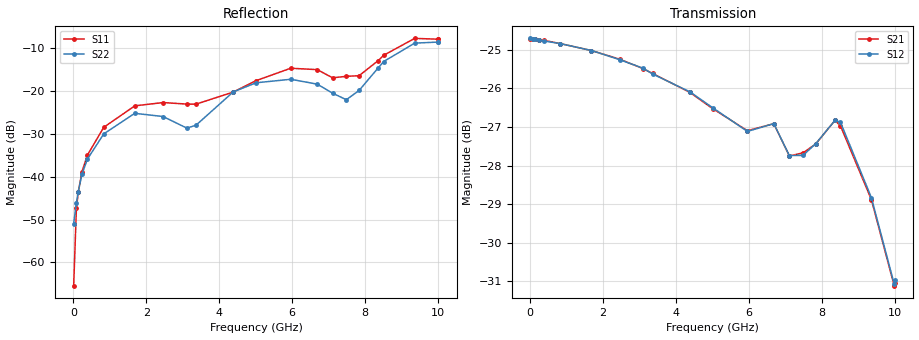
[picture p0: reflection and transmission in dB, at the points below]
! Device ID: PE43704
! Dir: z:\PE43704\PE43704_Char_1_20130516\PE43704\AMB\3p400V\23p75dB
! Serial: 14
! Insertion: A
! Impedance: 50 ohm
! Temp: Amb
! VDD: 3.400V
! Attenuation Step: 23.75dB
! IDD: 1.140316e-01mA
#  Hz  S  RI  R  50
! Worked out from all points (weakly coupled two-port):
!   401 points, 10 MHz to 10.01 GHz, reference 50 ohm
!   highest |S21| = -24.72 dB at 10 MHz (marker M1); lowest = -31.1 dB at 9.985 GHz (marker M2)
!   lowest |S11| = -65.4 dB at 10 MHz (marker M3), VSWR 1.00, Z = 50 + j0.0424 ohm
!   |S11| at or under -10 dB: start of sweep to 8.731 GHz
!   |S22| runs from -50.9 to -8.4 dB; largest |S21 - S12| = 0.00065
!   S11 on the Smith chart (normalised r, x): 10 MHz: 1.00, +0.00; 7.485 GHz: 0.78, +0.15; 8.51 GHz: 0.80, +0.45; 9.36 GHz: 0.53, +0.48; 10.01 GHz: 0.46, +0.27
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1e7  0.000328 0.000423  0.0581 -0.000172  0.0582 -0.000194  0.00281 0.000446
8.5e7  0.000398 0.00431  0.058 -0.00146  0.058 -0.00141  0.00308 0.00394
1.35e8  0.000192 0.00658  0.058 -0.0023  0.058 -0.00225  0.0028 0.00611
2.35e8  -0.00149 0.0113  0.0578 -0.00387  0.0578 -0.00382  0.0013 0.0106
3.85e8  -0.00458 0.0173  0.0575 -0.00634  0.0574 -0.00628  -0.00179 0.016
8.35e8  -0.0247 0.0288  0.0558 -0.013  0.0558 -0.013  -0.0196 0.025
1.685e9  -0.0659 0.0147  0.0504 -0.0247  0.0504 -0.0247  -0.0547 0.00782
2.46e9  -0.0735 -0.00674  0.0433 -0.0334  0.0432 -0.0334  -0.0503 -0.00641
3.11e9  -0.0705 -0.00719  0.036 -0.0391  0.0361 -0.0391  -0.0368 0.00516
3.36e9  -0.0706 -0.00139  0.0329 -0.0408  0.0329 -0.0407  -0.0374 0.0142
4.385e9  -0.0883 0.0422  0.0211 -0.0448  0.0211 -0.0449  -0.0792 0.0583
5.01e9  -0.1124 0.0712  0.0145 -0.0449  0.0146 -0.045  -0.1089 0.0626
5.96e9  -0.1603 0.0939  0.00496 -0.0439  0.00498 -0.0438  -0.1278 0.0522
6.685e9  -0.1603 0.0797  -0.00102 -0.0451  -0.00122 -0.0451  -0.1132 0.0433
7.11e9  -0.1301 0.061  -0.00739 -0.0403  -0.00767 -0.0403  -0.0799 0.0513
7.485e9  -0.1164 0.0937  -0.00781 -0.0406  -0.00774 -0.0403  -0.0506 0.0615
7.835e9  -0.0733 0.1332  -0.00986 -0.0413  -0.00961 -0.0414  -0.0364 0.0955
8.36e9  -0.0422 0.2244  -0.0192 -0.0413  -0.019 -0.0414  -0.0546 0.1798
8.51e9  -0.0455 0.2595  -0.0216 -0.0393  -0.0217 -0.0398  -0.0689 0.2118
9.36e9  -0.1882 0.3699  -0.0266 -0.0242  -0.0268 -0.0243  -0.233 0.281
9.985e9  -0.3187 0.2514  -0.018 -0.0212  -0.0181 -0.0213  -0.3556 0.1203
1.001e10  -0.324 0.2431  -0.0175 -0.0219  -0.0178 -0.022  -0.3597 0.1114
